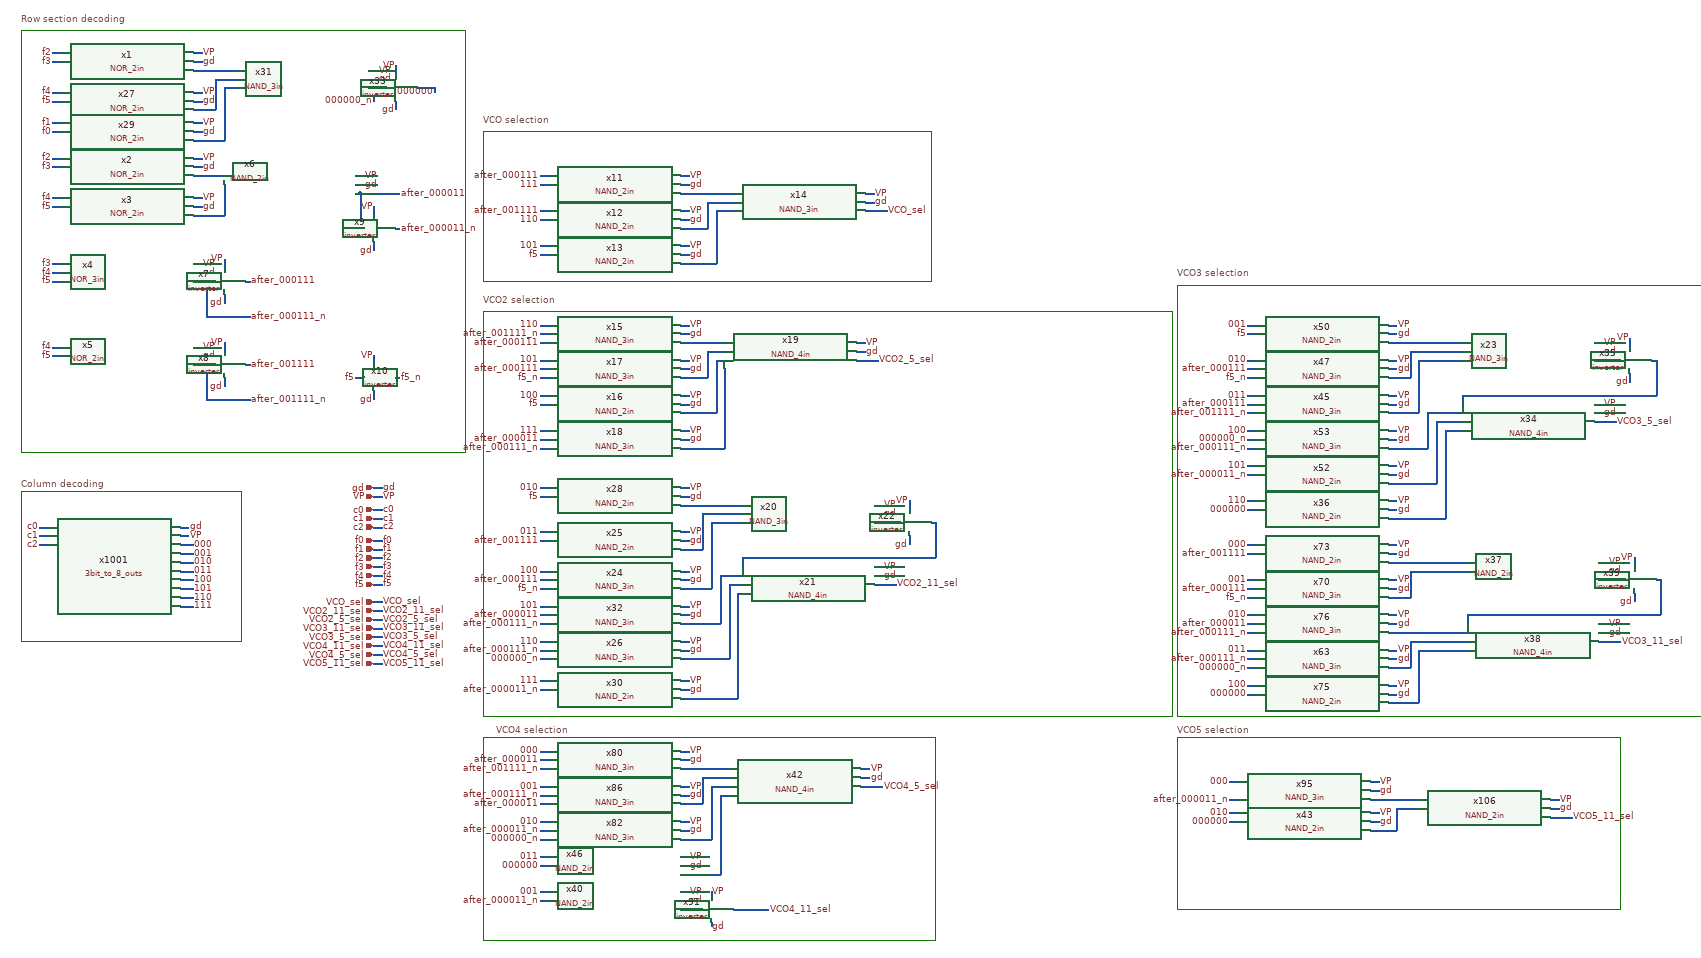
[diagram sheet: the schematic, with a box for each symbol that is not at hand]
v {xschem version=3.4.8RC file_version=1.3}
G {}
K {}
V {}
S {}
F {}
E {}
L 4 -160 -190 -160 150 {}
L 4 -160 -190 340 -190 {}
L 4 340 -190 340 150 {}
L 4 -160 150 340 150 {}
L 4 60 -280 400 -280 {}
L 4 400 -280 740 -280 {}
L 4 -160 -280 180 -280 {}
L 4 -160 -620 -160 -280 {}
L 4 -160 -1020 -160 -680 {}
L 4 850 -700 850 -360 {}
L 4 850 -1020 850 -680 {}
L 4 510 -280 850 -280 {}
L 4 60 -1240 400 -1240 {}
L 4 400 -1240 740 -1240 {}
L 4 -160 -1240 180 -1240 {}
L 4 510 -1240 850 -1240 {}
L 4 -160 -900 -160 -560 {}
L 4 850 -620 850 -280 {}
L 4 890 -1010 890 -670 {}
L 4 890 -670 1230 -670 {}
L 4 1230 -670 1570 -670 {}
L 4 1570 -670 1910 -670 {}
L 4 1910 -1010 1910 -670 {}
L 4 890 -1010 1230 -1010 {}
L 4 1230 -1010 1570 -1010 {}
L 4 1570 -1010 1910 -1010 {}
L 4 890 -600 890 -260 {}
L 4 890 -600 1230 -600 {}
L 4 1230 -600 1570 -600 {}
L 4 1570 -600 1910 -600 {}
L 4 890 -270 890 70 {}
L 4 890 -110 890 230 {}
L 4 890 320 1230 320 {}
L 4 1230 320 1570 320 {}
L 4 1570 320 1910 320 {}
L 4 1900 -600 2240 -600 {}
L 4 1890 320 2230 320 {}
L 4 2120 320 2460 320 {}
L 4 2460 -60 2460 280 {}
L 4 2460 -400 2460 -60 {}
L 4 2460 -600 2460 -260 {}
L 4 2120 -600 2460 -600 {}
L 4 2470 -120 2470 220 {}
L 4 2470 -460 2470 -120 {}
L 4 2470 -660 2470 -320 {}
L 4 2470 -190 2470 150 {}
L 4 4030 -410 4030 -70 {}
L 4 4030 -660 4030 -320 {}
L 4 4030 -190 4030 150 {}
L 4 2470 -660 2810 -660 {}
L 4 2810 -660 3150 -660 {}
L 4 3140 -660 3480 -660 {}
L 4 3360 -660 3700 -660 {}
L 4 2800 -660 3140 -660 {}
L 4 3140 -660 3480 -660 {}
L 4 3470 -660 3810 -660 {}
L 4 3690 -660 4030 -660 {}
L 4 2470 320 2810 320 {}
L 4 2800 320 3140 320 {}
L 4 3140 320 3480 320 {}
L 4 3470 320 3810 320 {}
L 4 3690 320 4030 320 {}
L 4 890 370 890 710 {}
L 4 1060 370 1400 370 {}
L 4 1380 370 1720 370 {}
L 4 1090 370 1430 370 {}
L 4 1430 370 1770 370 {}
L 4 1060 830 1400 830 {}
L 4 1380 830 1720 830 {}
L 4 1920 370 1920 710 {}
L 4 2470 420 2470 760 {}
L 4 2470 370 2470 710 {}
L 4 2470 370 2810 370 {}
L 4 2790 370 3130 370 {}
L 4 3120 370 3460 370 {}
L 4 2470 760 2810 760 {}
L 4 2790 760 3130 760 {}
L 4 3120 760 3460 760 {}
L 4 3480 420 3480 760 {}
L 4 -160 -1240 -160 -900 {}
L 4 850 -1240 850 -900 {}
L 4 890 -20 890 320 {}
L 4 2460 -20 2460 320 {}
L 4 2470 -20 2470 320 {}
L 4 4030 -20 4030 320 {}
L 4 890 490 890 830 {}
L 4 890 830 1230 830 {}
L 4 890 370 1230 370 {}
L 4 1920 490 1920 830 {}
L 4 1580 830 1920 830 {}
L 4 1580 370 1920 370 {}
L 4 3480 370 3480 710 {}
L 4 3140 370 3480 370 {}
L 4 3140 760 3480 760 {}
T {Column decoding} -160 -220 0 0 0.4 0.4 {}
T {Row section decoding} -160 -1280 0 0 0.4 0.4 {}
T {VCO selection} 890 -1050 0 0 0.4 0.4 {}
T {VCO2 selection} 890 -640 0 0 0.4 0.4 {}
T {VCO3 selection} 2470 -700 0 0 0.4 0.4 {}
T {VCO4 selection} 920 340 0 0 0.4 0.4 {}
T {VCO5 selection} 2470 340 0 0 0.4 0.4 {}
N 640 -200 660 -200 {lab=gd}
N 640 -180 660 -180 {lab=VP}
N 640 -130 660 -130 {lab=c1}
N 640 -110 660 -110 {lab=c2}
N 640 -80 660 -80 {lab=f0}
N 640 -60 660 -60 {lab=f1}
N 640 -150 660 -150 {lab=c0}
N 640 80 660 80 {lab=VCO2_11_sel}
N 640 100 660 100 {lab=VCO2_5_sel}
N 640 60 660 60 {lab=VCO_sel}
N 640 120 660 120 {lab=VCO3_11_sel}
N 640 140 660 140 {lab=VCO3_5_sel}
N 640 180 660 180 {lab=VCO4_5_sel}
N 640 200 660 200 {lab=VCO5_11_sel}
N 640 160 660 160 {lab=VCO4_11_sel}
N 640 -40 660 -40 {lab=f2}
N 640 -20 660 -20 {lab=f3}
N 640 0 660 0 {lab=f4}
N 640 20 660 20 {lab=f5}
N -120 -90 -100 -90 {lab=c1}
N -120 -70 -100 -70 {lab=c2}
N -120 -110 -100 -110 {lab=c0}
N 200 -90 220 -90 {lab=VP}
N 200 -110 220 -110 {lab=gd}
N 230 -930 250 -930 {lab=gd}
N 230 -950 250 -950 {lab=VP}
N 230 -840 250 -840 {lab=gd}
N 230 -860 250 -860 {lab=VP}
N 230 -690 250 -690 {lab=gd}
N 230 -710 250 -710 {lab=VP}
N 230 -500 250 -500 {lab=gd}
N 230 -520 250 -520 {lab=VP}
N 230 -910 300 -910 {lab=#net1}
N 300 -890 300 -820 {lab=#net2}
N 230 -820 300 -820 {lab=#net2}
N 600 -890 620 -890 {lab=gd}
N 600 -910 620 -910 {lab=VP}
N 300 -640 300 -620 {lab=gd}
N 300 -720 300 -700 {lab=VP}
N 260 -670 280 -670 {lab=after_000111_n}
N 260 -670 260 -590 {lab=after_000111_n}
N 230 -670 260 -670 {lab=after_000111_n}
N 260 -590 360 -590 {lab=after_000111_n}
N 300 -450 300 -430 {lab=gd}
N 300 -530 300 -510 {lab=VP}
N 260 -480 280 -480 {lab=after_001111_n}
N 260 -480 260 -400 {lab=after_001111_n}
N 230 -480 260 -480 {lab=after_001111_n}
N 260 -400 360 -400 {lab=after_001111_n}
N 350 -480 360 -480 {lab=after_001111}
N 350 -670 360 -670 {lab=after_000111}
N -90 -950 -70 -950 {lab=f2}
N -90 -930 -70 -930 {lab=f3}
N -90 -860 -70 -860 {lab=f4}
N -90 -840 -70 -840 {lab=f5}
N -90 -710 -70 -710 {lab=f3}
N -90 -690 -70 -690 {lab=f4}
N -90 -670 -70 -670 {lab=f5}
N -90 -520 -70 -520 {lab=f4}
N -90 -500 -70 -500 {lab=f5}
N 610 -870 700 -870 {lab=after_000011}
N 640 -760 640 -740 {lab=gd}
N 640 -840 640 -820 {lab=VP}
N 690 -790 700 -790 {lab=after_000011_n}
N 610 -870 610 -790 {lab=after_000011}
N 600 -870 610 -870 {lab=after_000011}
N 610 -790 620 -790 {lab=after_000011}
N 640 -420 640 -400 {lab=gd}
N 640 -500 640 -480 {lab=VP}
N 600 -450 620 -450 {lab=f5}
N 690 -450 700 -450 {lab=f5_n}
N 1340 -890 1360 -890 {lab=gd}
N 1340 -910 1360 -910 {lab=VP}
N 1340 -810 1360 -810 {lab=gd}
N 1340 -830 1360 -830 {lab=VP}
N 1340 -730 1360 -730 {lab=gd}
N 1340 -750 1360 -750 {lab=VP}
N 200 -70 230 -70 {lab=000}
N 200 -50 230 -50 {lab=001}
N 200 -30 230 -30 {lab=010}
N 200 -10 230 -10 {lab=011}
N 200 10 230 10 {lab=100}
N 200 30 230 30 {lab=101}
N 200 50 230 50 {lab=110}
N 200 70 230 70 {lab=111}
N 1020 -910 1040 -910 {lab=after_000111}
N 1020 -890 1040 -890 {lab=111}
N 1020 -830 1040 -830 {lab=after_001111}
N 1020 -810 1040 -810 {lab=110}
N 1020 -750 1040 -750 {lab=101}
N 1020 -730 1040 -730 {lab=f5}
N 1340 -870 1460 -870 {lab=#net3}
N 1400 -850 1460 -850 {lab=#net4}
N 1400 -850 1400 -790 {lab=#net4}
N 1340 -790 1400 -790 {lab=#net4}
N 1420 -830 1460 -830 {lab=#net5}
N 1340 -710 1420 -710 {lab=#net5}
N 1420 -830 1420 -710 {lab=#net5}
N 1760 -850 1780 -850 {lab=gd}
N 1760 -870 1780 -870 {lab=VP}
N 1760 -830 1810 -830 {lab=VCO_sel}
N 1340 -550 1360 -550 {lab=gd}
N 1340 -570 1360 -570 {lab=VP}
N 1340 -390 1360 -390 {lab=gd}
N 1340 -410 1360 -410 {lab=VP}
N 1340 -470 1360 -470 {lab=gd}
N 1340 -490 1360 -490 {lab=VP}
N 1340 -310 1360 -310 {lab=gd}
N 1340 -330 1360 -330 {lab=VP}
N 1020 -570 1040 -570 {lab=110}
N 1020 -550 1040 -550 {lab=after_001111_n}
N 1020 -530 1040 -530 {lab=after_000111}
N 1020 -490 1040 -490 {lab=101}
N 1020 -470 1040 -470 {lab=after_000111}
N 1020 -450 1040 -450 {lab=f5_n}
N 1020 -330 1040 -330 {lab=111}
N 1020 -290 1040 -290 {lab=after_000111_n}
N 1020 -410 1040 -410 {lab=100}
N 1020 -390 1040 -390 {lab=f5}
N 1340 -530 1440 -530 {lab=#net6}
N 1340 -450 1400 -450 {lab=#net7}
N 1400 -510 1400 -450 {lab=#net7}
N 1400 -510 1440 -510 {lab=#net7}
N 1420 -490 1440 -490 {lab=#net8}
N 1420 -490 1420 -370 {lab=#net8}
N 1340 -370 1420 -370 {lab=#net8}
N 1340 -290 1440 -290 {lab=#net9}
N 1440 -470 1440 -290 {lab=#net9}
N 1740 -510 1760 -510 {lab=gd}
N 1740 -530 1760 -530 {lab=VP}
N 1740 -490 1790 -490 {lab=VCO2_5_sel}
N 1780 -140 1800 -140 {lab=gd}
N 1780 -160 1800 -160 {lab=VP}
N 1340 10 1360 10 {lab=gd}
N 1340 -10 1360 -10 {lab=VP}
N 1340 -80 1360 -80 {lab=gd}
N 1340 -100 1360 -100 {lab=VP}
N 1340 30 1410 30 {lab=#net10}
N 1340 -60 1390 -60 {lab=#net11}
N 1340 -180 1360 -180 {lab=gd}
N 1340 -200 1360 -200 {lab=VP}
N 1340 260 1360 260 {lab=gd}
N 1340 240 1360 240 {lab=VP}
N 1340 280 1470 280 {lab=#net12}
N 1340 90 1360 90 {lab=gd}
N 1340 70 1360 70 {lab=VP}
N 1340 110 1430 110 {lab=#net13}
N 1020 -310 1040 -310 {lab=after_000011}
N 1020 -10 1040 -10 {lab=100}
N 1020 30 1040 30 {lab=f5_n}
N 1020 10 1040 10 {lab=after_000111}
N 1020 70 1040 70 {lab=101}
N 1020 110 1040 110 {lab=after_000111_n}
N 1020 90 1040 90 {lab=after_000011}
N 1020 -200 1040 -200 {lab=010}
N 1020 -180 1040 -180 {lab=f5}
N 1020 -100 1040 -100 {lab=011}
N 1020 -80 1040 -80 {lab=after_001111}
N 1020 240 1040 240 {lab=111}
N 1020 260 1040 260 {lab=after_000011_n}
N 1780 -120 1840 -120 {lab=#net14}
N 2910 560 2930 560 {lab=gd}
N 2910 540 2930 540 {lab=VP}
N 2590 540 2610 540 {lab=010}
N 2590 560 2610 560 {lab=000000}
N 2950 -390 2970 -390 {lab=gd}
N 2950 -410 2970 -410 {lab=VP}
N 2950 -370 3020 -370 {lab=#net15}
N 2630 -410 2650 -410 {lab=011}
N 2630 -370 2650 -370 {lab=after_001111_n}
N 2630 -390 2650 -390 {lab=after_000111}
N 2950 -470 2970 -470 {lab=gd}
N 2950 -490 2970 -490 {lab=VP}
N 2950 -450 3000 -450 {lab=#net16}
N 2630 -490 2650 -490 {lab=010}
N 2630 -450 2650 -450 {lab=f5_n}
N 2630 -470 2650 -470 {lab=after_000111}
N 2950 -550 2970 -550 {lab=gd}
N 2950 -570 2970 -570 {lab=VP}
N 2950 -530 3120 -530 {lab=#net17}
N 2630 -570 2650 -570 {lab=001}
N 2630 -550 2650 -550 {lab=f5}
N 2950 -230 2970 -230 {lab=gd}
N 2950 -250 2970 -250 {lab=VP}
N 2630 -250 2650 -250 {lab=101}
N 2630 -230 2650 -230 {lab=after_000011_n}
N 2950 -310 2970 -310 {lab=gd}
N 2950 -330 2970 -330 {lab=VP}
N 2950 -290 3040 -290 {lab=#net18}
N 2630 -330 2650 -330 {lab=100}
N 2630 -290 2650 -290 {lab=after_000111_n}
N 2630 -310 2650 -310 {lab=000000_n}
N 2950 -150 2970 -150 {lab=gd}
N 2950 -170 2970 -170 {lab=VP}
N 2950 -130 3080 -130 {lab=#net19}
N 2630 -170 2650 -170 {lab=110}
N 2630 -150 2650 -150 {lab=000000}
N 2950 190 2970 190 {lab=gd}
N 2950 170 2970 170 {lab=VP}
N 2950 210 3000 210 {lab=#net20}
N 2630 170 2650 170 {lab=011}
N 2630 190 2650 190 {lab=after_000111_n}
N 2950 30 2970 30 {lab=gd}
N 2950 10 2970 10 {lab=VP}
N 2950 50 3000 50 {lab=#net21}
N 2630 10 2650 10 {lab=001}
N 2630 50 2650 50 {lab=f5_n}
N 2630 30 2650 30 {lab=after_000111}
N 2950 -50 2970 -50 {lab=gd}
N 2950 -70 2970 -70 {lab=VP}
N 2950 -30 3130 -30 {lab=#net22}
N 2630 -70 2650 -70 {lab=000}
N 2630 -50 2650 -50 {lab=after_001111}
N 2950 270 2970 270 {lab=gd}
N 2950 250 2970 250 {lab=VP}
N 2950 290 3020 290 {lab=#net23}
N 2630 250 2650 250 {lab=100}
N 2630 270 2650 270 {lab=000000}
N 2950 110 2970 110 {lab=gd}
N 2950 90 2970 90 {lab=VP}
N 2950 130 3130 130 {lab=#net24}
N 2630 90 2650 90 {lab=010}
N 2630 130 2650 130 {lab=after_000111_n}
N 2630 110 2650 110 {lab=after_000011}
N 1340 420 1360 420 {lab=gd}
N 1340 400 1360 400 {lab=VP}
N 1340 440 1450 440 {lab=#net25}
N 1020 400 1040 400 {lab=000}
N 1020 440 1040 440 {lab=after_001111_n}
N 1020 420 1040 420 {lab=after_000011}
N 1340 580 1360 580 {lab=gd}
N 1340 560 1360 560 {lab=VP}
N 1340 600 1410 600 {lab=#net26}
N 1020 560 1040 560 {lab=010}
N 1020 600 1040 600 {lab=000000_n}
N 1020 580 1040 580 {lab=after_000011_n}
N 1340 660 1360 660 {lab=gd}
N 1340 640 1360 640 {lab=VP}
N 1340 680 1430 680 {lab=#net27}
N 1020 640 1040 640 {lab=011}
N 1020 660 1040 660 {lab=000000}
N 1340 500 1360 500 {lab=gd}
N 1340 480 1360 480 {lab=VP}
N 1340 520 1390 520 {lab=#net28}
N 1020 480 1040 480 {lab=001}
N 1020 520 1040 520 {lab=after_000011}
N 1340 740 1360 740 {lab=gd}
N 1340 720 1360 720 {lab=VP}
N 1410 790 1410 800 {lab=gd}
N 1410 720 1410 730 {lab=VP}
N 1340 760 1390 760 {lab=#net29}
N 1460 760 1540 760 {lab=VCO4_11_sel}
N 1020 720 1040 720 {lab=001}
N 1020 740 1040 740 {lab=after_000011_n}
N 2910 490 2930 490 {lab=gd}
N 2910 470 2930 470 {lab=VP}
N 2910 510 3020 510 {lab=#net30}
N 2590 470 2610 470 {lab=000}
N 2590 510 2610 510 {lab=after_000011_n}
N 3320 530 3340 530 {lab=gd}
N 3320 510 3340 510 {lab=VP}
N 3320 550 3370 550 {lab=VCO5_11_sel}
N 1340 170 1360 170 {lab=gd}
N 1340 150 1360 150 {lab=VP}
N 1020 150 1040 150 {lab=110}
N 1020 170 1040 170 {lab=after_000111_n}
N 230 -1170 250 -1170 {lab=gd}
N 230 -1190 250 -1190 {lab=VP}
N 230 -1080 250 -1080 {lab=gd}
N 230 -1100 250 -1100 {lab=VP}
N -90 -1190 -70 -1190 {lab=f2}
N -90 -1170 -70 -1170 {lab=f3}
N -90 -1100 -70 -1100 {lab=f4}
N -90 -1080 -70 -1080 {lab=f5}
N 230 -1010 250 -1010 {lab=gd}
N 230 -1030 250 -1030 {lab=VP}
N -90 -1030 -70 -1030 {lab=f1}
N -90 -1010 -70 -1010 {lab=f0}
N 630 -1130 650 -1130 {lab=gd}
N 630 -1150 650 -1150 {lab=VP}
N 230 -1150 330 -1150 {lab=#net31}
N 280 -1130 330 -1130 {lab=#net32}
N 280 -1130 280 -1060 {lab=#net32}
N 230 -1060 280 -1060 {lab=#net32}
N 230 -990 300 -990 {lab=#net33}
N 300 -1110 300 -990 {lab=#net33}
N 300 -1110 330 -1110 {lab=#net33}
N 690 -1080 690 -1060 {lab=gd}
N 690 -1160 690 -1140 {lab=VP}
N 740 -1110 780 -1110 {lab=000000}
N 780 -1110 780 -1100 {lab=000000}
N 640 -1110 670 -1110 {lab=000000_n}
N 640 -1110 640 -1080 {lab=000000_n}
N 630 -1110 640 -1110 {lab=000000_n}
N 1020 190 1040 190 {lab=000000_n}
N 1780 0 1800 0 {lab=gd}
N 1780 -20 1800 -20 {lab=VP}
N 1780 20 1830 20 {lab=VCO2_11_sel}
N 1860 -90 1860 -70 {lab=gd}
N 1860 -170 1860 -150 {lab=VP}
N 1910 -120 1920 -120 {lab=#net34}
N 1920 -120 1920 -40 {lab=#net34}
N 1480 -40 1920 -40 {lab=#net34}
N 1480 -40 1480 -20 {lab=#net34}
N 1340 -160 1480 -160 {lab=#net35}
N 1390 -140 1390 -60 {lab=#net11}
N 1390 -140 1480 -140 {lab=#net11}
N 1410 -120 1480 -120 {lab=#net10}
N 1410 -120 1410 30 {lab=#net10}
N 1430 0 1430 110 {lab=#net13}
N 1430 0 1480 -0 {lab=#net13}
N 1450 20 1480 20 {lab=#net36}
N 1450 20 1450 190 {lab=#net36}
N 1340 190 1450 190 {lab=#net36}
N 1470 40 1470 280 {lab=#net12}
N 1470 40 1480 40 {lab=#net12}
N 3420 -510 3440 -510 {lab=gd}
N 3420 -530 3440 -530 {lab=VP}
N 3420 -490 3480 -490 {lab=#net37}
N 3420 -370 3440 -370 {lab=gd}
N 3420 -390 3440 -390 {lab=VP}
N 3420 -350 3470 -350 {lab=VCO3_5_sel}
N 3500 -460 3500 -440 {lab=gd}
N 3500 -540 3500 -520 {lab=VP}
N 3550 -490 3560 -490 {lab=#net38}
N 3560 -490 3560 -410 {lab=#net38}
N 3120 -410 3560 -410 {lab=#net38}
N 3120 -410 3120 -390 {lab=#net38}
N 3000 -510 3000 -450 {lab=#net16}
N 3000 -510 3120 -510 {lab=#net16}
N 3020 -490 3120 -490 {lab=#net15}
N 3020 -490 3020 -370 {lab=#net15}
N 3040 -370 3040 -290 {lab=#net18}
N 3040 -370 3120 -370 {lab=#net18}
N 3060 -350 3120 -350 {lab=#net39}
N 3060 -350 3060 -210 {lab=#net39}
N 2950 -210 3060 -210 {lab=#net39}
N 3080 -330 3080 -130 {lab=#net19}
N 3080 -330 3120 -330 {lab=#net19}
N 3430 -10 3450 -10 {lab=gd}
N 3430 -30 3450 -30 {lab=VP}
N 3430 10 3490 10 {lab=#net40}
N 3430 130 3450 130 {lab=gd}
N 3430 110 3450 110 {lab=VP}
N 3430 150 3480 150 {lab=VCO3_11_sel}
N 3510 40 3510 60 {lab=gd}
N 3510 -40 3510 -20 {lab=VP}
N 3560 10 3570 10 {lab=#net41}
N 3570 10 3570 90 {lab=#net41}
N 3130 90 3570 90 {lab=#net41}
N 3130 90 3130 110 {lab=#net41}
N 3000 -10 3000 50 {lab=#net21}
N 3000 -10 3130 -10 {lab=#net21}
N 3000 150 3000 210 {lab=#net20}
N 3000 150 3130 150 {lab=#net20}
N 3020 170 3020 290 {lab=#net23}
N 3020 170 3130 170 {lab=#net23}
N 2630 210 2650 210 {lab=000000_n}
N 1750 460 1770 460 {lab=gd}
N 1750 440 1770 440 {lab=VP}
N 1750 480 1800 480 {lab=VCO4_5_sel}
N 1020 500 1040 500 {lab=after_000111_n}
N 1390 460 1390 520 {lab=#net28}
N 1390 460 1450 460 {lab=#net28}
N 1410 480 1450 480 {lab=#net26}
N 1410 480 1410 600 {lab=#net26}
N 1430 500 1430 680 {lab=#net27}
N 1430 500 1450 500 {lab=#net27}
N 2910 580 2970 580 {lab=#net42}
N 2970 530 2970 580 {lab=#net42}
N 2970 530 3020 530 {lab=#net42}
C {iopin.sym} 640 -200 2 0 {name=p46 lab=gd}
C {lab_wire.sym} 660 -200 2 0 {name=p53 sig_type=std_logic lab=gd}
C {iopin.sym} 640 -180 2 0 {name=p54 lab=VP}
C {ipin.sym} 640 -130 0 0 {name=p2 lab=c1}
C {lab_wire.sym} 660 -130 2 0 {name=p56 sig_type=std_logic lab=c1}
C {ipin.sym} 640 -110 0 0 {name=p57 lab=c2}
C {lab_wire.sym} 660 -110 2 0 {name=p58 sig_type=std_logic lab=c2}
C {ipin.sym} 640 -80 0 0 {name=p59 lab=f0}
C {lab_wire.sym} 660 -80 2 0 {name=p60 sig_type=std_logic lab=f0}
C {ipin.sym} 640 -60 0 0 {name=p61 lab=f1}
C {lab_wire.sym} 660 -60 2 0 {name=p63 sig_type=std_logic lab=f1}
C {ipin.sym} 640 -150 0 0 {name=p20 lab=c0}
C {lab_wire.sym} 660 -150 2 0 {name=p21 sig_type=std_logic lab=c0}
C {lab_wire.sym} 660 -180 2 0 {name=p1 sig_type=std_logic lab=VP}
C {opin.sym} 640 80 0 1 {name=p6 lab=VCO2_11_sel}
C {lab_wire.sym} 660 80 2 0 {name=p7 sig_type=std_logic lab=VCO2_11_sel}
C {opin.sym} 640 100 0 1 {name=p8 lab=VCO2_5_sel}
C {lab_wire.sym} 660 100 2 0 {name=p9 sig_type=std_logic lab=VCO2_5_sel}
C {opin.sym} 640 60 0 1 {name=p14 lab=VCO_sel}
C {lab_wire.sym} 660 60 2 0 {name=p15 sig_type=std_logic lab=VCO_sel}
C {opin.sym} 640 120 0 1 {name=p10 lab=VCO3_11_sel}
C {lab_wire.sym} 660 120 2 0 {name=p11 sig_type=std_logic lab=VCO3_11_sel}
C {opin.sym} 640 140 0 1 {name=p12 lab=VCO3_5_sel}
C {lab_wire.sym} 660 140 2 0 {name=p13 sig_type=std_logic lab=VCO3_5_sel}
C {opin.sym} 640 160 0 1 {name=p3 lab=VCO4_11_sel}
C {lab_wire.sym} 660 160 2 0 {name=p4 sig_type=std_logic lab=VCO4_11_sel}
C {opin.sym} 640 180 0 1 {name=p5 lab=VCO4_5_sel}
C {lab_wire.sym} 660 180 2 0 {name=p16 sig_type=std_logic lab=VCO4_5_sel}
C {opin.sym} 640 200 0 1 {name=p17 lab=VCO5_11_sel}
C {lab_wire.sym} 660 200 2 0 {name=p18 sig_type=std_logic lab=VCO5_11_sel}
C {ipin.sym} 640 -40 0 0 {name=p19 lab=f2}
C {lab_wire.sym} 660 -40 2 0 {name=p22 sig_type=std_logic lab=f2}
C {ipin.sym} 640 -20 0 0 {name=p23 lab=f3}
C {lab_wire.sym} 660 -20 2 0 {name=p24 sig_type=std_logic lab=f3}
C {ipin.sym} 640 0 0 0 {name=p25 lab=f4}
C {lab_wire.sym} 660 0 2 0 {name=p26 sig_type=std_logic lab=f4}
C {ipin.sym} 640 20 0 0 {name=p27 lab=f5}
C {lab_wire.sym} 660 20 2 0 {name=p28 sig_type=std_logic lab=f5}
C {/foss/designs/CHIP-PLL/schematics/divider/schematics/3bit_to_8_outs.sym} 50 -20 0 0 {name=x1001}
C {lab_wire.sym} -120 -90 0 0 {name=p29 sig_type=std_logic lab=c1}
C {lab_wire.sym} -120 -70 0 0 {name=p30 sig_type=std_logic lab=c2}
C {lab_wire.sym} -120 -110 0 0 {name=p31 sig_type=std_logic lab=c0}
C {lab_wire.sym} 220 -90 2 0 {name=p32 sig_type=std_logic lab=VP}
C {lab_wire.sym} 220 -110 2 0 {name=p33 sig_type=std_logic lab=gd}
C {/foss/designs/CHIP-PLL/schematics/divider/schematics/NOR_2in.sym} 80 -930 0 0 {name=x2}
C {/foss/designs/CHIP-PLL/schematics/divider/schematics/NOR_2in.sym} 80 -840 0 0 {name=x3}
C {/foss/designs/CHIP-PLL/schematics/divider/schematics/NOR_3in.sym} 80 -690 0 0 {name=x4}
C {/foss/designs/CHIP-PLL/schematics/divider/schematics/NOR_2in.sym} 80 -500 0 0 {name=x5}
C {lab_wire.sym} 250 -950 2 0 {name=p34 sig_type=std_logic lab=VP}
C {lab_wire.sym} 250 -930 2 0 {name=p35 sig_type=std_logic lab=gd}
C {lab_wire.sym} 250 -860 2 0 {name=p36 sig_type=std_logic lab=VP}
C {lab_wire.sym} 250 -840 2 0 {name=p37 sig_type=std_logic lab=gd}
C {lab_wire.sym} 250 -710 2 0 {name=p38 sig_type=std_logic lab=VP}
C {lab_wire.sym} 250 -690 2 0 {name=p39 sig_type=std_logic lab=gd}
C {lab_wire.sym} 250 -520 2 0 {name=p40 sig_type=std_logic lab=VP}
C {lab_wire.sym} 250 -500 2 0 {name=p41 sig_type=std_logic lab=gd}
C {/foss/designs/CHIP-PLL/schematics/divider/schematics/NAND_2in.sym} 450 -890 0 0 {name=x6}
C {lab_wire.sym} 620 -910 2 0 {name=p42 sig_type=std_logic lab=VP}
C {lab_wire.sym} 620 -890 2 0 {name=p43 sig_type=std_logic lab=gd}
C {/foss/designs/CHIP-PLL/schematics/divider/schematics/inverter.sym} 300 -670 0 0 {name=x7}
C {lab_wire.sym} 300 -620 3 0 {name=p44 sig_type=std_logic lab=gd}
C {lab_wire.sym} 300 -720 1 0 {name=p45 sig_type=std_logic lab=VP}
C {/foss/designs/CHIP-PLL/schematics/divider/schematics/inverter.sym} 300 -480 0 0 {name=x8}
C {lab_wire.sym} 300 -430 3 0 {name=p47 sig_type=std_logic lab=gd}
C {lab_wire.sym} 300 -530 1 0 {name=p48 sig_type=std_logic lab=VP}
C {lab_wire.sym} -90 -950 0 0 {name=p49 sig_type=std_logic lab=f2}
C {lab_wire.sym} -90 -710 0 0 {name=p50 sig_type=std_logic lab=f3}
C {lab_wire.sym} -90 -690 0 0 {name=p51 sig_type=std_logic lab=f4}
C {lab_wire.sym} -90 -670 0 0 {name=p52 sig_type=std_logic lab=f5}
C {lab_wire.sym} -90 -860 0 0 {name=p62 sig_type=std_logic lab=f4}
C {lab_wire.sym} -90 -840 0 0 {name=p64 sig_type=std_logic lab=f5}
C {lab_wire.sym} -90 -930 0 0 {name=p65 sig_type=std_logic lab=f3}
C {lab_wire.sym} -90 -520 0 0 {name=p66 sig_type=std_logic lab=f4}
C {lab_wire.sym} -90 -500 0 0 {name=p67 sig_type=std_logic lab=f5}
C {/foss/designs/CHIP-PLL/schematics/divider/schematics/inverter.sym} 640 -790 0 0 {name=x9}
C {lab_wire.sym} 640 -740 3 0 {name=p68 sig_type=std_logic lab=gd}
C {lab_wire.sym} 640 -840 1 0 {name=p69 sig_type=std_logic lab=VP}
C {lab_wire.sym} 700 -870 2 0 {name=p70 sig_type=std_logic lab=after_000011}
C {lab_wire.sym} 700 -790 2 0 {name=p71 sig_type=std_logic lab=after_000011_n}
C {lab_wire.sym} 360 -670 2 0 {name=p72 sig_type=std_logic lab=after_000111}
C {lab_wire.sym} 360 -590 2 0 {name=p73 sig_type=std_logic lab=after_000111_n}
C {lab_wire.sym} 360 -480 2 0 {name=p74 sig_type=std_logic lab=after_001111}
C {lab_wire.sym} 360 -400 2 0 {name=p75 sig_type=std_logic lab=after_001111_n}
C {/foss/designs/CHIP-PLL/schematics/divider/schematics/inverter.sym} 640 -450 0 0 {name=x10}
C {lab_wire.sym} 640 -400 3 0 {name=p79 sig_type=std_logic lab=gd}
C {lab_wire.sym} 640 -500 1 0 {name=p80 sig_type=std_logic lab=VP}
C {lab_wire.sym} 700 -450 2 0 {name=p81 sig_type=std_logic lab=f5_n}
C {lab_wire.sym} 600 -450 0 0 {name=p83 sig_type=std_logic lab=f5}
C {/foss/designs/CHIP-PLL/schematics/divider/schematics/NAND_2in.sym} 1190 -890 0 0 {name=x11}
C {lab_wire.sym} 1360 -910 2 0 {name=p84 sig_type=std_logic lab=VP}
C {lab_wire.sym} 1360 -890 2 0 {name=p85 sig_type=std_logic lab=gd}
C {/foss/designs/CHIP-PLL/schematics/divider/schematics/NAND_2in.sym} 1190 -810 0 0 {name=x12}
C {lab_wire.sym} 1360 -830 2 0 {name=p86 sig_type=std_logic lab=VP}
C {lab_wire.sym} 1360 -810 2 0 {name=p87 sig_type=std_logic lab=gd}
C {/foss/designs/CHIP-PLL/schematics/divider/schematics/NAND_2in.sym} 1190 -730 0 0 {name=x13}
C {lab_wire.sym} 1360 -750 2 0 {name=p88 sig_type=std_logic lab=VP}
C {lab_wire.sym} 1360 -730 2 0 {name=p89 sig_type=std_logic lab=gd}
C {lab_wire.sym} 1020 -910 0 0 {name=p101 sig_type=std_logic lab=after_000111}
C {lab_wire.sym} 1020 -830 0 0 {name=p103 sig_type=std_logic lab=after_001111}
C {lab_wire.sym} 230 -70 2 0 {name=p105 sig_type=std_logic lab=000}
C {lab_wire.sym} 230 -50 2 0 {name=p106 sig_type=std_logic lab=001}
C {lab_wire.sym} 230 -10 2 0 {name=p107 sig_type=std_logic lab=011}
C {lab_wire.sym} 230 10 2 0 {name=p108 sig_type=std_logic lab=100}
C {lab_wire.sym} 230 30 2 0 {name=p109 sig_type=std_logic lab=101}
C {lab_wire.sym} 230 50 2 0 {name=p110 sig_type=std_logic lab=110}
C {lab_wire.sym} 230 70 2 0 {name=p111 sig_type=std_logic lab=111}
C {lab_wire.sym} 230 -30 2 0 {name=p112 sig_type=std_logic lab=010}
C {lab_wire.sym} 1020 -750 0 0 {name=p119 sig_type=std_logic lab=101}
C {lab_wire.sym} 1020 -810 0 0 {name=p120 sig_type=std_logic lab=110}
C {lab_wire.sym} 1020 -890 0 0 {name=p123 sig_type=std_logic lab=111}
C {lab_wire.sym} 1020 -490 0 0 {name=p124 sig_type=std_logic lab=101}
C {lab_wire.sym} 1020 -570 0 0 {name=p125 sig_type=std_logic lab=110}
C {lab_wire.sym} 1020 -730 0 0 {name=p126 sig_type=std_logic lab=f5}
C {/foss/designs/CHIP-PLL/schematics/divider/schematics/NAND_3in.sym} 1610 -850 0 0 {name=x14}
C {lab_wire.sym} 1780 -870 2 0 {name=p127 sig_type=std_logic lab=VP}
C {lab_wire.sym} 1780 -850 2 0 {name=p128 sig_type=std_logic lab=gd}
C {lab_wire.sym} 1810 -830 2 0 {name=p129 sig_type=std_logic lab=VCO_sel}
C {/foss/designs/CHIP-PLL/schematics/divider/schematics/NAND_3in.sym} 1190 -550 0 0 {name=x15}
C {/foss/designs/CHIP-PLL/schematics/divider/schematics/NAND_2in.sym} 1190 -390 0 0 {name=x16}
C {lab_wire.sym} 1360 -570 2 0 {name=p130 sig_type=std_logic lab=VP}
C {lab_wire.sym} 1360 -550 2 0 {name=p131 sig_type=std_logic lab=gd}
C {lab_wire.sym} 1360 -410 2 0 {name=p132 sig_type=std_logic lab=VP}
C {lab_wire.sym} 1360 -390 2 0 {name=p133 sig_type=std_logic lab=gd}
C {/foss/designs/CHIP-PLL/schematics/divider/schematics/NAND_3in.sym} 1190 -470 0 0 {name=x17}
C {lab_wire.sym} 1360 -490 2 0 {name=p134 sig_type=std_logic lab=VP}
C {lab_wire.sym} 1360 -470 2 0 {name=p135 sig_type=std_logic lab=gd}
C {/foss/designs/CHIP-PLL/schematics/divider/schematics/NAND_3in.sym} 1190 -310 0 0 {name=x18}
C {lab_wire.sym} 1360 -330 2 0 {name=p136 sig_type=std_logic lab=VP}
C {lab_wire.sym} 1360 -310 2 0 {name=p137 sig_type=std_logic lab=gd}
C {lab_wire.sym} 1020 -410 0 0 {name=p140 sig_type=std_logic lab=100}
C {lab_wire.sym} 1020 -330 0 0 {name=p141 sig_type=std_logic lab=111}
C {lab_wire.sym} 1020 -550 0 0 {name=p142 sig_type=std_logic lab=after_001111_n}
C {lab_wire.sym} 1020 -530 0 0 {name=p145 sig_type=std_logic lab=after_000111}
C {lab_wire.sym} 1020 -470 0 0 {name=p146 sig_type=std_logic lab=after_000111}
C {lab_wire.sym} 1020 -450 0 0 {name=p147 sig_type=std_logic lab=f5_n}
C {lab_wire.sym} 1020 -390 0 0 {name=p90 sig_type=std_logic lab=f5}
C {lab_wire.sym} 1020 -310 0 0 {name=p91 sig_type=std_logic lab=after_000011}
C {lab_wire.sym} 1020 -290 0 0 {name=p94 sig_type=std_logic lab=after_000111_n}
C {/foss/designs/CHIP-PLL/schematics/divider/schematics/NAND_4in.sym} 1590 -500 0 0 {name=x19}
C {lab_wire.sym} 1760 -530 2 0 {name=p148 sig_type=std_logic lab=VP}
C {lab_wire.sym} 1760 -510 2 0 {name=p149 sig_type=std_logic lab=gd}
C {lab_wire.sym} 1790 -490 2 0 {name=p150 sig_type=std_logic lab=VCO2_5_sel}
C {/foss/designs/CHIP-PLL/schematics/divider/schematics/NAND_3in.sym} 1630 -140 0 0 {name=x20}
C {lab_wire.sym} 1800 -160 2 0 {name=p157 sig_type=std_logic lab=VP}
C {lab_wire.sym} 1800 -140 2 0 {name=p158 sig_type=std_logic lab=gd}
C {/foss/designs/CHIP-PLL/schematics/divider/schematics/NAND_3in.sym} 1190 10 0 0 {name=x24}
C {lab_wire.sym} 1360 -10 2 0 {name=p159 sig_type=std_logic lab=VP}
C {lab_wire.sym} 1360 10 2 0 {name=p160 sig_type=std_logic lab=gd}
C {/foss/designs/CHIP-PLL/schematics/divider/schematics/NAND_2in.sym} 1190 -80 0 0 {name=x25}
C {lab_wire.sym} 1360 -100 2 0 {name=p161 sig_type=std_logic lab=VP}
C {lab_wire.sym} 1360 -80 2 0 {name=p162 sig_type=std_logic lab=gd}
C {/foss/designs/CHIP-PLL/schematics/divider/schematics/NAND_2in.sym} 1190 -180 0 0 {name=x28}
C {lab_wire.sym} 1360 -200 2 0 {name=p167 sig_type=std_logic lab=VP}
C {lab_wire.sym} 1360 -180 2 0 {name=p168 sig_type=std_logic lab=gd}
C {/foss/designs/CHIP-PLL/schematics/divider/schematics/NAND_2in.sym} 1190 260 0 0 {name=x30}
C {lab_wire.sym} 1360 240 2 0 {name=p171 sig_type=std_logic lab=VP}
C {lab_wire.sym} 1360 260 2 0 {name=p172 sig_type=std_logic lab=gd}
C {/foss/designs/CHIP-PLL/schematics/divider/schematics/NAND_3in.sym} 1190 90 0 0 {name=x32}
C {lab_wire.sym} 1360 70 2 0 {name=p175 sig_type=std_logic lab=VP}
C {lab_wire.sym} 1360 90 2 0 {name=p176 sig_type=std_logic lab=gd}
C {lab_wire.sym} 1020 -10 0 0 {name=p193 sig_type=std_logic lab=100}
C {lab_wire.sym} 1020 -100 0 0 {name=p194 sig_type=std_logic lab=011}
C {lab_wire.sym} 1020 -200 0 0 {name=p195 sig_type=std_logic lab=010}
C {lab_wire.sym} 1020 240 0 0 {name=p196 sig_type=std_logic lab=111}
C {lab_wire.sym} 1020 70 0 0 {name=p197 sig_type=std_logic lab=101}
C {lab_wire.sym} 1020 10 0 0 {name=p198 sig_type=std_logic lab=after_000111}
C {lab_wire.sym} 1020 30 0 0 {name=p201 sig_type=std_logic lab=f5_n}
C {lab_wire.sym} 1020 -80 0 0 {name=p202 sig_type=std_logic lab=after_001111}
C {lab_wire.sym} 1020 -180 0 0 {name=p203 sig_type=std_logic lab=f5}
C {lab_wire.sym} 1020 260 0 0 {name=p204 sig_type=std_logic lab=after_000011_n}
C {lab_wire.sym} 1020 90 0 0 {name=p205 sig_type=std_logic lab=after_000011}
C {lab_wire.sym} 1020 110 0 0 {name=p206 sig_type=std_logic lab=after_000111_n}
C {lab_wire.sym} 2930 540 2 0 {name=p217 sig_type=std_logic lab=VP}
C {lab_wire.sym} 2930 560 2 0 {name=p218 sig_type=std_logic lab=gd}
C {/foss/designs/CHIP-PLL/schematics/divider/schematics/NAND_2in.sym} 2760 560 0 0 {name=x43}
C {/foss/designs/CHIP-PLL/schematics/divider/schematics/NAND_3in.sym} 2800 -390 0 0 {name=x45}
C {lab_wire.sym} 2970 -410 2 0 {name=p221 sig_type=std_logic lab=VP}
C {lab_wire.sym} 2970 -390 2 0 {name=p222 sig_type=std_logic lab=gd}
C {/foss/designs/CHIP-PLL/schematics/divider/schematics/NAND_3in.sym} 2800 -470 0 0 {name=x47}
C {lab_wire.sym} 2970 -490 2 0 {name=p225 sig_type=std_logic lab=VP}
C {lab_wire.sym} 2970 -470 2 0 {name=p226 sig_type=std_logic lab=gd}
C {lab_wire.sym} 2970 -570 2 0 {name=p229 sig_type=std_logic lab=VP}
C {lab_wire.sym} 2970 -550 2 0 {name=p230 sig_type=std_logic lab=gd}
C {/foss/designs/CHIP-PLL/schematics/divider/schematics/NAND_2in.sym} 2800 -550 0 0 {name=x50}
C {lab_wire.sym} 2970 -250 2 0 {name=p233 sig_type=std_logic lab=VP}
C {lab_wire.sym} 2970 -230 2 0 {name=p234 sig_type=std_logic lab=gd}
C {/foss/designs/CHIP-PLL/schematics/divider/schematics/NAND_2in.sym} 2800 -230 0 0 {name=x52}
C {/foss/designs/CHIP-PLL/schematics/divider/schematics/NAND_3in.sym} 2800 -310 0 0 {name=x53}
C {lab_wire.sym} 2970 -330 2 0 {name=p237 sig_type=std_logic lab=VP}
C {lab_wire.sym} 2970 -310 2 0 {name=p238 sig_type=std_logic lab=gd}
C {lab_wire.sym} 2970 -170 2 0 {name=p241 sig_type=std_logic lab=VP}
C {lab_wire.sym} 2970 -150 2 0 {name=p242 sig_type=std_logic lab=gd}
C {lab_wire.sym} 2630 -410 0 0 {name=p253 sig_type=std_logic lab=011}
C {lab_wire.sym} 2630 -490 0 0 {name=p254 sig_type=std_logic lab=010}
C {lab_wire.sym} 2630 -250 0 0 {name=p256 sig_type=std_logic lab=101}
C {lab_wire.sym} 2630 -170 0 0 {name=p257 sig_type=std_logic lab=110}
C {lab_wire.sym} 2630 -330 0 0 {name=p258 sig_type=std_logic lab=100}
C {lab_wire.sym} 2630 -390 0 0 {name=p263 sig_type=std_logic lab=after_000111}
C {lab_wire.sym} 2630 -370 0 0 {name=p264 sig_type=std_logic lab=after_001111_n}
C {lab_wire.sym} 2630 -470 0 0 {name=p265 sig_type=std_logic lab=after_000111}
C {lab_wire.sym} 2630 -450 0 0 {name=p266 sig_type=std_logic lab=f5_n}
C {lab_wire.sym} 2630 -550 0 0 {name=p267 sig_type=std_logic lab=f5}
C {lab_wire.sym} 2630 -230 0 0 {name=p268 sig_type=std_logic lab=after_000011_n}
C {lab_wire.sym} 2630 -290 0 0 {name=p270 sig_type=std_logic lab=after_000111_n}
C {/foss/designs/CHIP-PLL/schematics/divider/schematics/NAND_3in.sym} 2800 190 0 0 {name=x63}
C {lab_wire.sym} 2970 170 2 0 {name=p275 sig_type=std_logic lab=VP}
C {lab_wire.sym} 2970 190 2 0 {name=p276 sig_type=std_logic lab=gd}
C {/foss/designs/CHIP-PLL/schematics/divider/schematics/NAND_3in.sym} 2800 30 0 0 {name=x70}
C {lab_wire.sym} 2970 10 2 0 {name=p289 sig_type=std_logic lab=VP}
C {lab_wire.sym} 2970 30 2 0 {name=p290 sig_type=std_logic lab=gd}
C {lab_wire.sym} 2970 -70 2 0 {name=p293 sig_type=std_logic lab=VP}
C {lab_wire.sym} 2970 -50 2 0 {name=p294 sig_type=std_logic lab=gd}
C {/foss/designs/CHIP-PLL/schematics/divider/schematics/NAND_2in.sym} 2800 -50 0 0 {name=x73}
C {lab_wire.sym} 2970 250 2 0 {name=p297 sig_type=std_logic lab=VP}
C {lab_wire.sym} 2970 270 2 0 {name=p298 sig_type=std_logic lab=gd}
C {/foss/designs/CHIP-PLL/schematics/divider/schematics/NAND_2in.sym} 2800 270 0 0 {name=x75}
C {/foss/designs/CHIP-PLL/schematics/divider/schematics/NAND_3in.sym} 2800 110 0 0 {name=x76}
C {lab_wire.sym} 2970 90 2 0 {name=p301 sig_type=std_logic lab=VP}
C {lab_wire.sym} 2970 110 2 0 {name=p302 sig_type=std_logic lab=gd}
C {lab_wire.sym} 2630 10 0 0 {name=p307 sig_type=std_logic lab=001}
C {lab_wire.sym} 2630 -70 0 0 {name=p308 sig_type=std_logic lab=000}
C {lab_wire.sym} 2630 250 0 0 {name=p311 sig_type=std_logic lab=100}
C {lab_wire.sym} 2630 90 0 0 {name=p312 sig_type=std_logic lab=010}
C {lab_wire.sym} 2630 170 0 0 {name=p313 sig_type=std_logic lab=011}
C {lab_wire.sym} 2630 30 0 0 {name=p315 sig_type=std_logic lab=after_000111}
C {lab_wire.sym} 2630 50 0 0 {name=p316 sig_type=std_logic lab=f5_n}
C {lab_wire.sym} 2630 -50 0 0 {name=p317 sig_type=std_logic lab=after_001111}
C {lab_wire.sym} 2630 110 0 0 {name=p319 sig_type=std_logic lab=after_000011}
C {lab_wire.sym} 2630 130 0 0 {name=p320 sig_type=std_logic lab=after_000111_n}
C {/foss/designs/CHIP-PLL/schematics/divider/schematics/NAND_3in.sym} 1190 420 0 0 {name=x80}
C {lab_wire.sym} 1360 400 2 0 {name=p327 sig_type=std_logic lab=VP}
C {lab_wire.sym} 1360 420 2 0 {name=p328 sig_type=std_logic lab=gd}
C {/foss/designs/CHIP-PLL/schematics/divider/schematics/NAND_3in.sym} 1190 580 0 0 {name=x82}
C {lab_wire.sym} 1360 560 2 0 {name=p331 sig_type=std_logic lab=VP}
C {lab_wire.sym} 1360 580 2 0 {name=p332 sig_type=std_logic lab=gd}
C {lab_wire.sym} 1360 640 2 0 {name=p335 sig_type=std_logic lab=VP}
C {lab_wire.sym} 1360 660 2 0 {name=p336 sig_type=std_logic lab=gd}
C {/foss/designs/CHIP-PLL/schematics/divider/schematics/NAND_3in.sym} 1190 500 0 0 {name=x86}
C {lab_wire.sym} 1360 480 2 0 {name=p339 sig_type=std_logic lab=VP}
C {lab_wire.sym} 1360 500 2 0 {name=p340 sig_type=std_logic lab=gd}
C {lab_wire.sym} 1360 720 2 0 {name=p347 sig_type=std_logic lab=VP}
C {lab_wire.sym} 1360 740 2 0 {name=p348 sig_type=std_logic lab=gd}
C {/foss/designs/CHIP-PLL/schematics/divider/schematics/inverter.sym} 1410 760 0 0 {name=x91}
C {lab_wire.sym} 1410 720 0 1 {name=p349 sig_type=std_logic lab=VP}
C {lab_wire.sym} 1410 800 2 0 {name=p350 sig_type=std_logic lab=gd}
C {lab_wire.sym} 1020 400 0 0 {name=p357 sig_type=std_logic lab=000}
C {lab_wire.sym} 1020 560 0 0 {name=p358 sig_type=std_logic lab=010}
C {lab_wire.sym} 1020 640 0 0 {name=p363 sig_type=std_logic lab=011}
C {lab_wire.sym} 1020 480 0 0 {name=p364 sig_type=std_logic lab=001}
C {lab_wire.sym} 1540 760 2 0 {name=p369 sig_type=std_logic lab=VCO4_11_sel}
C {lab_wire.sym} 1020 440 0 0 {name=p371 sig_type=std_logic lab=after_001111_n}
C {lab_wire.sym} 1020 420 0 0 {name=p372 sig_type=std_logic lab=after_000011}
C {lab_wire.sym} 1020 580 0 0 {name=p373 sig_type=std_logic lab=after_000011_n}
C {/foss/designs/CHIP-PLL/schematics/divider/schematics/NAND_3in.sym} 2760 490 0 0 {name=x95}
C {lab_wire.sym} 2930 470 2 0 {name=p390 sig_type=std_logic lab=VP}
C {lab_wire.sym} 2930 490 2 0 {name=p391 sig_type=std_logic lab=gd}
C {lab_wire.sym} 3370 550 2 0 {name=p389 sig_type=std_logic lab=VCO5_11_sel}
C {lab_wire.sym} 3340 510 2 0 {name=p400 sig_type=std_logic lab=VP}
C {lab_wire.sym} 3340 530 2 0 {name=p401 sig_type=std_logic lab=gd}
C {/foss/designs/CHIP-PLL/schematics/divider/schematics/NAND_2in.sym} 3170 530 0 0 {name=x106}
C {lab_wire.sym} 2590 470 0 0 {name=p216 sig_type=std_logic lab=000}
C {lab_wire.sym} 2590 510 0 0 {name=p402 sig_type=std_logic lab=after_000011_n}
C {lab_wire.sym} 2590 560 0 0 {name=p407 sig_type=std_logic lab=000000}
C {lab_wire.sym} 2590 540 0 0 {name=p408 sig_type=std_logic lab=010}
C {lab_wire.sym} 2630 -570 0 0 {name=p55 sig_type=std_logic lab=001}
C {/foss/designs/CHIP-PLL/schematics/divider/schematics/NAND_3in.sym} 1190 170 0 0 {name=x26}
C {lab_wire.sym} 1360 150 2 0 {name=p92 sig_type=std_logic lab=VP}
C {lab_wire.sym} 1360 170 2 0 {name=p93 sig_type=std_logic lab=gd}
C {lab_wire.sym} 1020 150 0 0 {name=p95 sig_type=std_logic lab=110}
C {lab_wire.sym} 1020 170 0 0 {name=p96 sig_type=std_logic lab=after_000111_n}
C {/foss/designs/CHIP-PLL/schematics/divider/schematics/NOR_2in.sym} 80 -1170 0 0 {name=x1}
C {/foss/designs/CHIP-PLL/schematics/divider/schematics/NOR_2in.sym} 80 -1080 0 0 {name=x27}
C {lab_wire.sym} 250 -1190 2 0 {name=p76 sig_type=std_logic lab=VP}
C {lab_wire.sym} 250 -1170 2 0 {name=p77 sig_type=std_logic lab=gd}
C {lab_wire.sym} 250 -1100 2 0 {name=p78 sig_type=std_logic lab=VP}
C {lab_wire.sym} 250 -1080 2 0 {name=p82 sig_type=std_logic lab=gd}
C {lab_wire.sym} -90 -1190 0 0 {name=p97 sig_type=std_logic lab=f2}
C {lab_wire.sym} -90 -1100 0 0 {name=p98 sig_type=std_logic lab=f4}
C {lab_wire.sym} -90 -1080 0 0 {name=p99 sig_type=std_logic lab=f5}
C {lab_wire.sym} -90 -1170 0 0 {name=p100 sig_type=std_logic lab=f3}
C {/foss/designs/CHIP-PLL/schematics/divider/schematics/NOR_2in.sym} 80 -1010 0 0 {name=x29}
C {lab_wire.sym} 250 -1030 2 0 {name=p102 sig_type=std_logic lab=VP}
C {lab_wire.sym} 250 -1010 2 0 {name=p104 sig_type=std_logic lab=gd}
C {lab_wire.sym} -90 -1030 0 0 {name=p113 sig_type=std_logic lab=f1}
C {lab_wire.sym} -90 -1010 0 0 {name=p114 sig_type=std_logic lab=f0}
C {/foss/designs/CHIP-PLL/schematics/divider/schematics/NAND_3in.sym} 480 -1130 0 0 {name=x31}
C {lab_wire.sym} 650 -1150 2 0 {name=p115 sig_type=std_logic lab=VP}
C {lab_wire.sym} 650 -1130 2 0 {name=p116 sig_type=std_logic lab=gd}
C {/foss/designs/CHIP-PLL/schematics/divider/schematics/inverter.sym} 690 -1110 0 0 {name=x33}
C {lab_wire.sym} 690 -1060 3 0 {name=p117 sig_type=std_logic lab=gd}
C {lab_wire.sym} 690 -1160 1 0 {name=p118 sig_type=std_logic lab=VP}
C {lab_wire.sym} 780 -1100 3 0 {name=p121 sig_type=std_logic lab=000000}
C {lab_wire.sym} 640 -1080 3 0 {name=p122 sig_type=std_logic lab=000000_n}
C {lab_wire.sym} 1020 190 0 0 {name=p138 sig_type=std_logic lab=000000_n}
C {/foss/designs/CHIP-PLL/schematics/divider/schematics/NAND_4in.sym} 1630 10 0 0 {name=x21}
C {lab_wire.sym} 1800 -20 2 0 {name=p139 sig_type=std_logic lab=VP}
C {lab_wire.sym} 1800 0 2 0 {name=p143 sig_type=std_logic lab=gd}
C {lab_wire.sym} 1830 20 2 0 {name=p144 sig_type=std_logic lab=VCO2_11_sel}
C {/foss/designs/CHIP-PLL/schematics/divider/schematics/inverter.sym} 1860 -120 0 0 {name=x22}
C {lab_wire.sym} 1860 -70 3 0 {name=p151 sig_type=std_logic lab=gd}
C {lab_wire.sym} 1860 -170 1 0 {name=p152 sig_type=std_logic lab=VP}
C {lab_wire.sym} 3470 -350 2 0 {name=p153 sig_type=std_logic lab=VCO3_5_sel}
C {/foss/designs/CHIP-PLL/schematics/divider/schematics/NAND_3in.sym} 3270 -510 0 0 {name=x23}
C {lab_wire.sym} 3440 -530 2 0 {name=p154 sig_type=std_logic lab=VP}
C {lab_wire.sym} 3440 -510 2 0 {name=p155 sig_type=std_logic lab=gd}
C {/foss/designs/CHIP-PLL/schematics/divider/schematics/NAND_4in.sym} 3270 -360 0 0 {name=x34}
C {lab_wire.sym} 3440 -390 2 0 {name=p156 sig_type=std_logic lab=VP}
C {lab_wire.sym} 3440 -370 2 0 {name=p163 sig_type=std_logic lab=gd}
C {/foss/designs/CHIP-PLL/schematics/divider/schematics/inverter.sym} 3500 -490 0 0 {name=x35}
C {lab_wire.sym} 3500 -440 3 0 {name=p165 sig_type=std_logic lab=gd}
C {lab_wire.sym} 3500 -540 1 0 {name=p166 sig_type=std_logic lab=VP}
C {lab_wire.sym} 2630 -310 0 0 {name=p164 sig_type=std_logic lab=000000_n}
C {lab_wire.sym} 2630 -150 0 0 {name=p169 sig_type=std_logic lab=000000}
C {/foss/designs/CHIP-PLL/schematics/divider/schematics/NAND_2in.sym} 2800 -150 0 0 {name=x36}
C {lab_wire.sym} 3450 -30 2 0 {name=p173 sig_type=std_logic lab=VP}
C {lab_wire.sym} 3450 -10 2 0 {name=p174 sig_type=std_logic lab=gd}
C {/foss/designs/CHIP-PLL/schematics/divider/schematics/NAND_4in.sym} 3280 140 0 0 {name=x38}
C {lab_wire.sym} 3450 110 2 0 {name=p177 sig_type=std_logic lab=VP}
C {lab_wire.sym} 3450 130 2 0 {name=p178 sig_type=std_logic lab=gd}
C {/foss/designs/CHIP-PLL/schematics/divider/schematics/inverter.sym} 3510 10 0 0 {name=x39}
C {lab_wire.sym} 3510 60 3 0 {name=p179 sig_type=std_logic lab=gd}
C {lab_wire.sym} 3510 -40 1 0 {name=p180 sig_type=std_logic lab=VP}
C {/foss/designs/CHIP-PLL/schematics/divider/schematics/NAND_2in.sym} 3280 -10 0 0 {name=x37}
C {lab_wire.sym} 3480 150 2 0 {name=p170 sig_type=std_logic lab=VCO3_11_sel}
C {lab_wire.sym} 2630 190 0 0 {name=p181 sig_type=std_logic lab=after_000111_n}
C {lab_wire.sym} 2630 210 0 0 {name=p182 sig_type=std_logic lab=000000_n}
C {lab_wire.sym} 2630 270 0 0 {name=p183 sig_type=std_logic lab=000000}
C {lab_wire.sym} 1020 720 0 0 {name=p184 sig_type=std_logic lab=001}
C {/foss/designs/CHIP-PLL/schematics/divider/schematics/NAND_2in.sym} 1190 740 0 0 {name=x40}
C {lab_wire.sym} 1020 740 0 0 {name=p185 sig_type=std_logic lab=after_000011_n}
C {/foss/designs/CHIP-PLL/schematics/divider/schematics/NAND_4in.sym} 1600 470 0 0 {name=x42}
C {lab_wire.sym} 1770 440 2 0 {name=p186 sig_type=std_logic lab=VP}
C {lab_wire.sym} 1770 460 2 0 {name=p187 sig_type=std_logic lab=gd}
C {lab_wire.sym} 1800 480 2 0 {name=p188 sig_type=std_logic lab=VCO4_5_sel}
C {lab_wire.sym} 1020 520 0 0 {name=p189 sig_type=std_logic lab=after_000011}
C {lab_wire.sym} 1020 500 0 0 {name=p190 sig_type=std_logic lab=after_000111_n}
C {/foss/designs/CHIP-PLL/schematics/divider/schematics/NAND_2in.sym} 1190 660 0 0 {name=x46}
C {lab_wire.sym} 1020 660 0 0 {name=p191 sig_type=std_logic lab=000000}
C {lab_wire.sym} 1020 600 0 0 {name=p192 sig_type=std_logic lab=000000_n}
